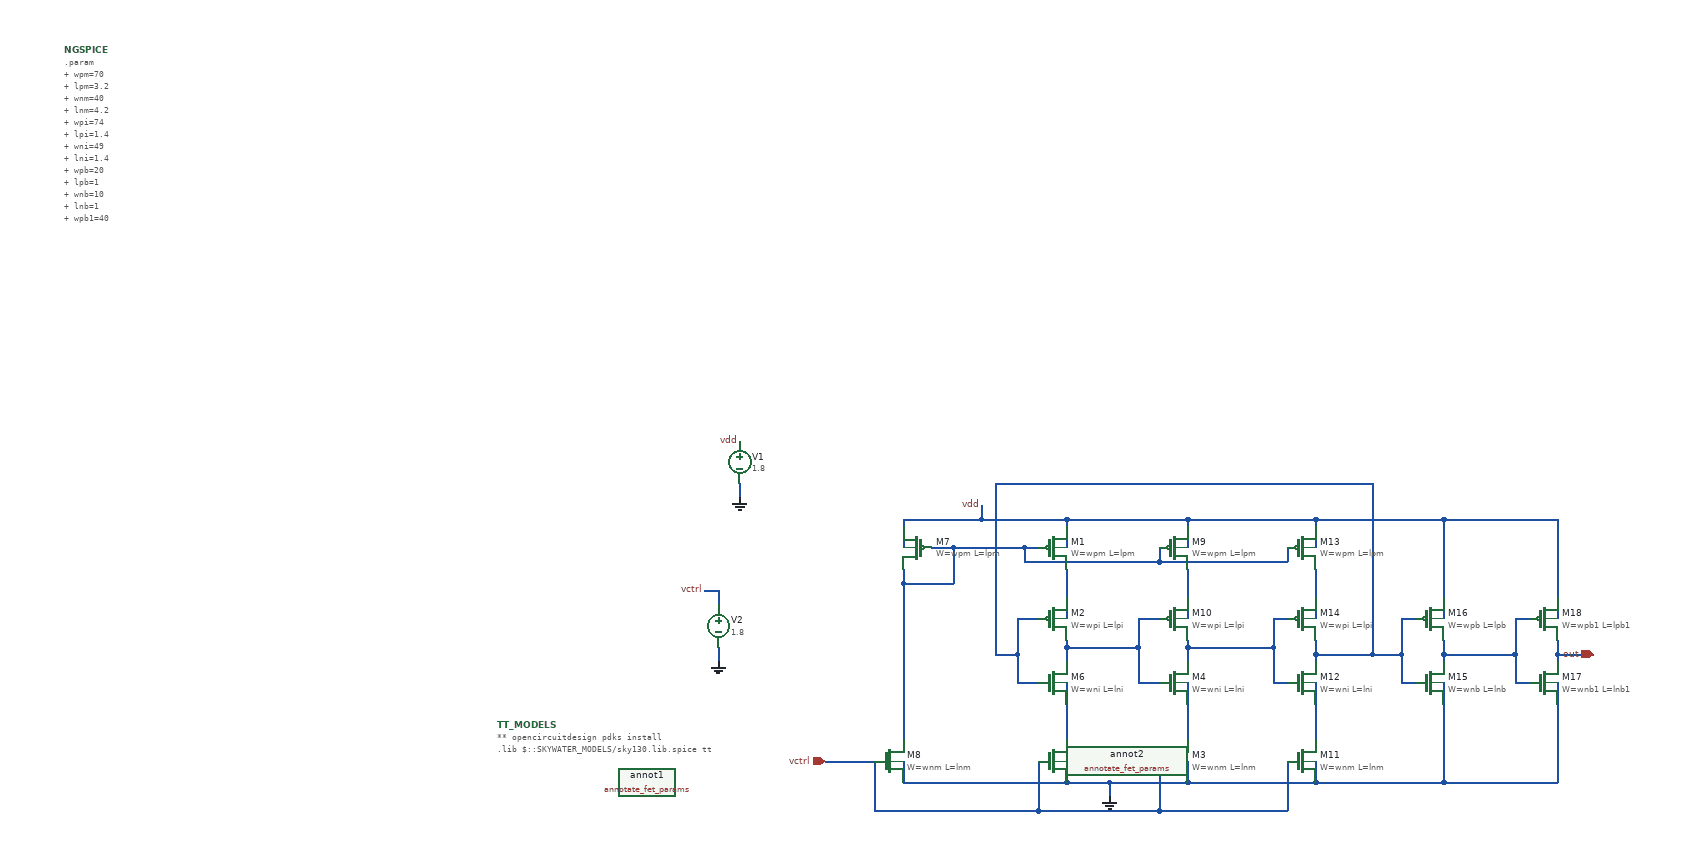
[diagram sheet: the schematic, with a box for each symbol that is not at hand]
v {xschem version=3.4.8RC file_version=1.3}
G {}
K {}
V {}
S {}
F {}
E {}
B 2 1740 -570 2540 -170 {flags=graph
y1=-0.23748273
y2=1.9945999
ypos1=0
ypos2=2
divy=5
subdivy=1
unity=1
x1=1.9499922e-06
x2=2.0097598e-06
divx=5
subdivx=1
xlabmag=1.0
ylabmag=1.0
node=out
color=4
dataset=-1
unitx=1
logx=0
logy=0
hilight_wave=0}
N 1450 130 1450 150 {lab=#net1}
N 1450 20 1450 90 {lab=#net2}
N 1380 140 1380 180 {lab=#net3}
N 1380 90 1410 90 {lab=#net3}
N 1390 -10 1410 -10 {lab=#net4}
N 1220 40 1290 40 {lab=#net4}
N 1290 -10 1290 40 {lab=#net4}
N 1410 290 1410 360 {lab=vctrl}
N 1180 290 1180 360 {lab=vctrl}
N 1110 290 1180 290 {lab=vctrl}
N 1220 290 1220 320 {lab=0}
N 1220 320 1450 320 {lab=0}
N 1450 290 1450 320 {lab=0}
N 1380 180 1410 180 {lab=#net3}
N 1220 -50 1220 -10 {lab=vdd}
N 1330 -50 1450 -50 {lab=vdd}
N 1450 -50 1450 -10 {lab=vdd}
N 1620 20 1620 90 {lab=#net5}
N 1580 290 1580 360 {lab=vctrl}
N 1620 290 1620 320 {lab=0}
N 1620 -50 1620 -10 {lab=vdd}
N 1450 130 1550 130 {lab=#net1}
N 1550 90 1550 130 {lab=#net1}
N 1550 90 1580 90 {lab=#net1}
N 1550 130 1550 180 {lab=#net1}
N 1550 180 1580 180 {lab=#net1}
N 1450 -50 1620 -50 {lab=vdd}
N 1800 20 1800 90 {lab=#net6}
N 1760 290 1760 360 {lab=vctrl}
N 1800 290 1800 320 {lab=0}
N 1800 -50 1800 -10 {lab=vdd}
N 1620 130 1740 130 {lab=#net7}
N 1740 90 1740 130 {lab=#net7}
N 1740 90 1760 90 {lab=#net7}
N 1740 130 1740 180 {lab=#net7}
N 1740 180 1760 180 {lab=#net7}
N 1880 140 1920 140 {lab=#net3}
N 1350 -100 1350 140 {lab=#net3}
N 1350 140 1380 140 {lab=#net3}
N 1620 320 1800 320 {lab=0}
N 1580 360 1760 360 {lab=vctrl}
N 1220 40 1220 260 {lab=#net4}
N 1330 -70 1330 -50 {lab=vdd}
N 1620 -50 1800 -50 {lab=vdd}
N 1450 180 1450 270 {lab=#net8}
N 990 -100 990 -80 {lab=0}
N 940 50 960 50 {lab=vctrl}
N 960 50 960 70 {lab=vctrl}
N 960 130 960 150 {lab=0}
N 1390 -10 1390 10 {lab=#net4}
N 1390 10 1580 10 {lab=#net4}
N 1580 -10 1580 10 {lab=#net4}
N 1580 10 1760 10 {lab=#net4}
N 1760 -10 1760 10 {lab=#net4}
N 1620 130 1620 150 {lab=#net7}
N 1620 180 1620 270 {lab=#net9}
N 1800 140 1800 150 {lab=#net3}
N 1800 180 1800 270 {lab=#net10}
N 1880 -100 1880 140 {lab=#net3}
N 1920 90 1920 140 {lab=#net3}
N 1920 90 1940 90 {lab=#net3}
N 1920 140 1920 180 {lab=#net3}
N 1920 180 1940 180 {lab=#net3}
N 1980 140 1980 150 {lab=#net11}
N 1980 180 1980 320 {lab=0}
N 1980 140 2080 140 {lab=#net11}
N 1980 -50 1980 90 {lab=vdd}
N 1800 -50 1980 -50 {lab=vdd}
N 1350 -100 1880 -100 {lab=#net3}
N 2080 90 2080 140 {lab=#net11}
N 2080 90 2100 90 {lab=#net11}
N 2080 140 2080 180 {lab=#net11}
N 2080 180 2100 180 {lab=#net11}
N 2140 140 2140 150 {lab=out}
N 2140 180 2140 320 {lab=0}
N 2140 140 2190 140 {lab=out}
N 1980 -50 2140 -50 {lab=vdd}
N 2140 -50 2140 90 {lab=vdd}
N 1980 320 2140 320 {lab=0}
N 1220 20 1220 40 {lab=#net4}
N 1260 -10 1290 -10 {lab=#net4}
N 1180 360 1410 360 {lab=vctrl}
N 1220 -50 1330 -50 {lab=vdd}
N 1410 360 1580 360 {lab=vctrl}
N 1510 320 1620 320 {lab=0}
N 1450 120 1450 130 {lab=#net1}
N 1620 120 1620 130 {lab=#net7}
N 1800 120 1800 140 {lab=#net3}
N 1380 90 1380 140 {lab=#net3}
N 1450 320 1510 320 {lab=0}
N 1290 -10 1390 -10 {lab=#net4}
N 1800 140 1880 140 {lab=#net3}
N 1980 120 1980 140 {lab=#net11}
N 1800 320 1980 320 {lab=0}
N 2140 120 2140 140 {lab=out}
N 1510 320 1510 340 {lab=0}
C {sky130_fd_pr/pfet_01v8.sym} 1240 -10 0 1 {name=M7
W="wpm"
L="lpm"
nf=1
mult=1
ad="expr('int((@nf + 1)/2) * @W / @nf * 0.29')"
pd="expr('2*int((@nf + 1)/2) * (@W / @nf + 0.29)')"
as="expr('int((@nf + 2)/2) * @W / @nf * 0.29')"
ps="expr('2*int((@nf + 2)/2) * (@W / @nf + 0.29)')"
nrd="expr('0.29 / @W ')" nrs="expr('0.29 / @W ')"
sa=0 sb=0 sd=0
model=pfet_01v8
spiceprefix=X
}
C {sky130_fd_pr/nfet_01v8.sym} 1200 290 0 0 {name=M8
W="wnm"
L="lnm"
nf=1 
mult=1
ad="expr('int((@nf + 1)/2) * @W / @nf * 0.29')"
pd="expr('2*int((@nf + 1)/2) * (@W / @nf + 0.29)')"
as="expr('int((@nf + 2)/2) * @W / @nf * 0.29')"
ps="expr('2*int((@nf + 2)/2) * (@W / @nf + 0.29)')"
nrd="expr('0.29 / @W ')" nrs="expr('0.29 / @W ')"
sa=0 sb=0 sd=0
model=nfet_01v8
spiceprefix=X
}
C {sky130_fd_pr/nfet_01v8.sym} 1430 290 0 0 {name=M5
W="wnm"
L="lnm"
nf=1 
mult=1
ad="expr('int((@nf + 1)/2) * @W / @nf * 0.29')"
pd="expr('2*int((@nf + 1)/2) * (@W / @nf + 0.29)')"
as="expr('int((@nf + 2)/2) * @W / @nf * 0.29')"
ps="expr('2*int((@nf + 2)/2) * (@W / @nf + 0.29)')"
nrd="expr('0.29 / @W ')" nrs="expr('0.29 / @W ')"
sa=0 sb=0 sd=0
model=nfet_01v8
spiceprefix=X
}
C {sky130_fd_pr/nfet_01v8.sym} 1430 180 0 0 {name=M6
W="wni"
L="lni"
nf=1 
mult=1
ad="expr('int((@nf + 1)/2) * @W / @nf * 0.29')"
pd="expr('2*int((@nf + 1)/2) * (@W / @nf + 0.29)')"
as="expr('int((@nf + 2)/2) * @W / @nf * 0.29')"
ps="expr('2*int((@nf + 2)/2) * (@W / @nf + 0.29)')"
nrd="expr('0.29 / @W ')" nrs="expr('0.29 / @W ')"
sa=0 sb=0 sd=0
model=nfet_01v8
spiceprefix=X
}
C {sky130_fd_pr/pfet_01v8.sym} 1430 -10 0 0 {name=M1
W="wpm"
L="lpm"
nf=1
mult=1
ad="expr('int((@nf + 1)/2) * @W / @nf * 0.29')"
pd="expr('2*int((@nf + 1)/2) * (@W / @nf + 0.29)')"
as="expr('int((@nf + 2)/2) * @W / @nf * 0.29')"
ps="expr('2*int((@nf + 2)/2) * (@W / @nf + 0.29)')"
nrd="expr('0.29 / @W ')" nrs="expr('0.29 / @W ')"
sa=0 sb=0 sd=0
model=pfet_01v8
spiceprefix=X
}
C {sky130_fd_pr/pfet_01v8.sym} 1430 90 0 0 {name=M2
W="wpi"
L="lpi"
nf=1
mult=1
ad="expr('int((@nf + 1)/2) * @W / @nf * 0.29')"
pd="expr('2*int((@nf + 1)/2) * (@W / @nf + 0.29)')"
as="expr('int((@nf + 2)/2) * @W / @nf * 0.29')"
ps="expr('2*int((@nf + 2)/2) * (@W / @nf + 0.29)')"
nrd="expr('0.29 / @W ')" nrs="expr('0.29 / @W ')"
sa=0 sb=0 sd=0
model=pfet_01v8
spiceprefix=X
}
C {sky130_fd_pr/nfet_01v8.sym} 1600 290 0 0 {name=M3
W="wnm"
L="lnm"
nf=1 
mult=1
ad="expr('int((@nf + 1)/2) * @W / @nf * 0.29')"
pd="expr('2*int((@nf + 1)/2) * (@W / @nf + 0.29)')"
as="expr('int((@nf + 2)/2) * @W / @nf * 0.29')"
ps="expr('2*int((@nf + 2)/2) * (@W / @nf + 0.29)')"
nrd="expr('0.29 / @W ')" nrs="expr('0.29 / @W ')"
sa=0 sb=0 sd=0
model=nfet_01v8
spiceprefix=X
}
C {sky130_fd_pr/pfet_01v8.sym} 1600 -10 0 0 {name=M9
W="wpm"
L="lpm"
nf=1
mult=1
ad="expr('int((@nf + 1)/2) * @W / @nf * 0.29')"
pd="expr('2*int((@nf + 1)/2) * (@W / @nf + 0.29)')"
as="expr('int((@nf + 2)/2) * @W / @nf * 0.29')"
ps="expr('2*int((@nf + 2)/2) * (@W / @nf + 0.29)')"
nrd="expr('0.29 / @W ')" nrs="expr('0.29 / @W ')"
sa=0 sb=0 sd=0
model=pfet_01v8
spiceprefix=X
}
C {sky130_fd_pr/nfet_01v8.sym} 1780 290 0 0 {name=M11
W="wnm"
L="lnm"
nf=1 
mult=1
ad="expr('int((@nf + 1)/2) * @W / @nf * 0.29')"
pd="expr('2*int((@nf + 1)/2) * (@W / @nf + 0.29)')"
as="expr('int((@nf + 2)/2) * @W / @nf * 0.29')"
ps="expr('2*int((@nf + 2)/2) * (@W / @nf + 0.29)')"
nrd="expr('0.29 / @W ')" nrs="expr('0.29 / @W ')"
sa=0 sb=0 sd=0
model=nfet_01v8
spiceprefix=X
}
C {sky130_fd_pr/pfet_01v8.sym} 1780 -10 0 0 {name=M13
W="wpm"
L="lpm"
nf=1
mult=1
ad="expr('int((@nf + 1)/2) * @W / @nf * 0.29')"
pd="expr('2*int((@nf + 1)/2) * (@W / @nf + 0.29)')"
as="expr('int((@nf + 2)/2) * @W / @nf * 0.29')"
ps="expr('2*int((@nf + 2)/2) * (@W / @nf + 0.29)')"
nrd="expr('0.29 / @W ')" nrs="expr('0.29 / @W ')"
sa=0 sb=0 sd=0
model=pfet_01v8
spiceprefix=X
}
C {ipin.sym} 1110 290 0 0 {name=p1 lab=vctrl}
C {iopin.sym} 2190 140 0 0 {name=p2 lab=out}
C {code_shown.sym} 40 -710 0 0 {name=NGSPICE only_toplevel=false value="
.param
+ wpm=70
+ lpm=3.2
+ wnm=40
+ lnm=4.2
+ wpi=74
+ lpi=1.4
+ wni=49
+ lni=1.4
+ wpb=20
+ lpb=1
+ wnb=10
+ lnb=1
+ wpb1=40
+ lpb1=1
+ wnb1=20
+ lnb1=1

.control
    let start_v = 0.7
    let stop_v = 1.2
    let step_v = 0.05
    let current_v = start_v
    
    * Create empty vectors to store our table data
    let v_points = unitvec(11) * 0
    let f_points = unitvec(11) * 0
    let index = 0

    while current_v <= stop_v + 0.01
        alter V2 $&current_v
        tran 1n 2u
        
        meas tran t_p trig v(out) val=0.9 rise=2 targ v(out) val=0.9 rise=3
        
        * Store values in our vectors
        let v_points[index] = current_v
        let f_points[index] = 1/t_p
        
        let current_v = current_v + step_v
        let index = index + 1
    end

    * Print the final table
    print v_points f_points
.endc
"}
C {gnd.sym} 1510 340 0 0 {name=l2 lab=0}
C {vsource.sym} 990 -130 0 0 {name=V1 value=1.8 savecurrent=false}
C {lab_pin.sym} 990 -160 0 0 {name=p4 sig_type=std_logic lab=vdd}
C {gnd.sym} 990 -80 0 0 {name=l3 lab=0}
C {vsource.sym} 960 100 0 0 {name=V2 value=1.8 savecurrent=false}
C {gnd.sym} 960 150 0 0 {name=l4 lab=0}
C {sky130_fd_pr/nfet_01v8.sym} 1600 180 0 0 {name=M4
W="wni"
L="lni"
nf=1 
mult=1
ad="expr('int((@nf + 1)/2) * @W / @nf * 0.29')"
pd="expr('2*int((@nf + 1)/2) * (@W / @nf + 0.29)')"
as="expr('int((@nf + 2)/2) * @W / @nf * 0.29')"
ps="expr('2*int((@nf + 2)/2) * (@W / @nf + 0.29)')"
nrd="expr('0.29 / @W ')" nrs="expr('0.29 / @W ')"
sa=0 sb=0 sd=0
model=nfet_01v8
spiceprefix=X
}
C {sky130_fd_pr/pfet_01v8.sym} 1600 90 0 0 {name=M10
W="wpi"
L="lpi"
nf=1
mult=1
ad="expr('int((@nf + 1)/2) * @W / @nf * 0.29')"
pd="expr('2*int((@nf + 1)/2) * (@W / @nf + 0.29)')"
as="expr('int((@nf + 2)/2) * @W / @nf * 0.29')"
ps="expr('2*int((@nf + 2)/2) * (@W / @nf + 0.29)')"
nrd="expr('0.29 / @W ')" nrs="expr('0.29 / @W ')"
sa=0 sb=0 sd=0
model=pfet_01v8
spiceprefix=X
}
C {sky130_fd_pr/nfet_01v8.sym} 1780 180 0 0 {name=M12
W="wni"
L="lni"
nf=1 
mult=1
ad="expr('int((@nf + 1)/2) * @W / @nf * 0.29')"
pd="expr('2*int((@nf + 1)/2) * (@W / @nf + 0.29)')"
as="expr('int((@nf + 2)/2) * @W / @nf * 0.29')"
ps="expr('2*int((@nf + 2)/2) * (@W / @nf + 0.29)')"
nrd="expr('0.29 / @W ')" nrs="expr('0.29 / @W ')"
sa=0 sb=0 sd=0
model=nfet_01v8
spiceprefix=X
}
C {sky130_fd_pr/pfet_01v8.sym} 1780 90 0 0 {name=M14
W="wpi"
L="lpi"
nf=1
mult=1
ad="expr('int((@nf + 1)/2) * @W / @nf * 0.29')"
pd="expr('2*int((@nf + 1)/2) * (@W / @nf + 0.29)')"
as="expr('int((@nf + 2)/2) * @W / @nf * 0.29')"
ps="expr('2*int((@nf + 2)/2) * (@W / @nf + 0.29)')"
nrd="expr('0.29 / @W ')" nrs="expr('0.29 / @W ')"
sa=0 sb=0 sd=0
model=pfet_01v8
spiceprefix=X
}
C {lab_pin.sym} 940 50 0 0 {name=p5 sig_type=std_logic lab=vctrl}
C {lab_pin.sym} 1330 -70 0 0 {name=p3 sig_type=std_logic lab=vdd}
C {devices/code.sym} 650 240 0 0 {name=TT_MODELS
only_toplevel=true
format="tcleval( @value )"
value="
** opencircuitdesign pdks install
.lib $::SKYWATER_MODELS/sky130.lib.spice tt
"
spice_ignore=false}
C {sky130_fd_pr/annotate_fet_params.sym} 860 320 0 0 {name=annot1 ref=M7}
C {sky130_fd_pr/annotate_fet_params.sym} 950 320 0 0 {name=annot2 ref=M8}
C {sky130_fd_pr/nfet_01v8.sym} 1960 180 0 0 {name=M15
W="wnb"
L="lnb"
nf=1 
mult=1
ad="expr('int((@nf + 1)/2) * @W / @nf * 0.29')"
pd="expr('2*int((@nf + 1)/2) * (@W / @nf + 0.29)')"
as="expr('int((@nf + 2)/2) * @W / @nf * 0.29')"
ps="expr('2*int((@nf + 2)/2) * (@W / @nf + 0.29)')"
nrd="expr('0.29 / @W ')" nrs="expr('0.29 / @W ')"
sa=0 sb=0 sd=0
model=nfet_01v8
spiceprefix=X
}
C {sky130_fd_pr/pfet_01v8.sym} 1960 90 0 0 {name=M16
W="wpb"
L="lpb"
nf=1
mult=1
ad="expr('int((@nf + 1)/2) * @W / @nf * 0.29')"
pd="expr('2*int((@nf + 1)/2) * (@W / @nf + 0.29)')"
as="expr('int((@nf + 2)/2) * @W / @nf * 0.29')"
ps="expr('2*int((@nf + 2)/2) * (@W / @nf + 0.29)')"
nrd="expr('0.29 / @W ')" nrs="expr('0.29 / @W ')"
sa=0 sb=0 sd=0
model=pfet_01v8
spiceprefix=X
}
C {sky130_fd_pr/nfet_01v8.sym} 2120 180 0 0 {name=M17
W="wnb1"
L="lnb1"
nf=1 
mult=1
ad="expr('int((@nf + 1)/2) * @W / @nf * 0.29')"
pd="expr('2*int((@nf + 1)/2) * (@W / @nf + 0.29)')"
as="expr('int((@nf + 2)/2) * @W / @nf * 0.29')"
ps="expr('2*int((@nf + 2)/2) * (@W / @nf + 0.29)')"
nrd="expr('0.29 / @W ')" nrs="expr('0.29 / @W ')"
sa=0 sb=0 sd=0
model=nfet_01v8
spiceprefix=X
}
C {sky130_fd_pr/pfet_01v8.sym} 2120 90 0 0 {name=M18
W="wpb1"
L="lpb1"
nf=1
mult=1
ad="expr('int((@nf + 1)/2) * @W / @nf * 0.29')"
pd="expr('2*int((@nf + 1)/2) * (@W / @nf + 0.29)')"
as="expr('int((@nf + 2)/2) * @W / @nf * 0.29')"
ps="expr('2*int((@nf + 2)/2) * (@W / @nf + 0.29)')"
nrd="expr('0.29 / @W ')" nrs="expr('0.29 / @W ')"
sa=0 sb=0 sd=0
model=pfet_01v8
spiceprefix=X
}
C {launcher.sym} 1530 -260 0 0 {name=h5
descr="load waves"
tclcommand="xschem raw_read $netlist_dir/vco_tb.raw tran"
}
